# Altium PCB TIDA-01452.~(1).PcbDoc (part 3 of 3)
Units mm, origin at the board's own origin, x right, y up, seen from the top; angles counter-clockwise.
Board outline 60 x 40 mm, 6 copper layers (Top Layer, IN1-GND, IN2, IN3-POWER, IN4-GND, Bottom Layer), stack 1.532 mm thick; 268 components, 172 nets, 850 pads, 525 vias.

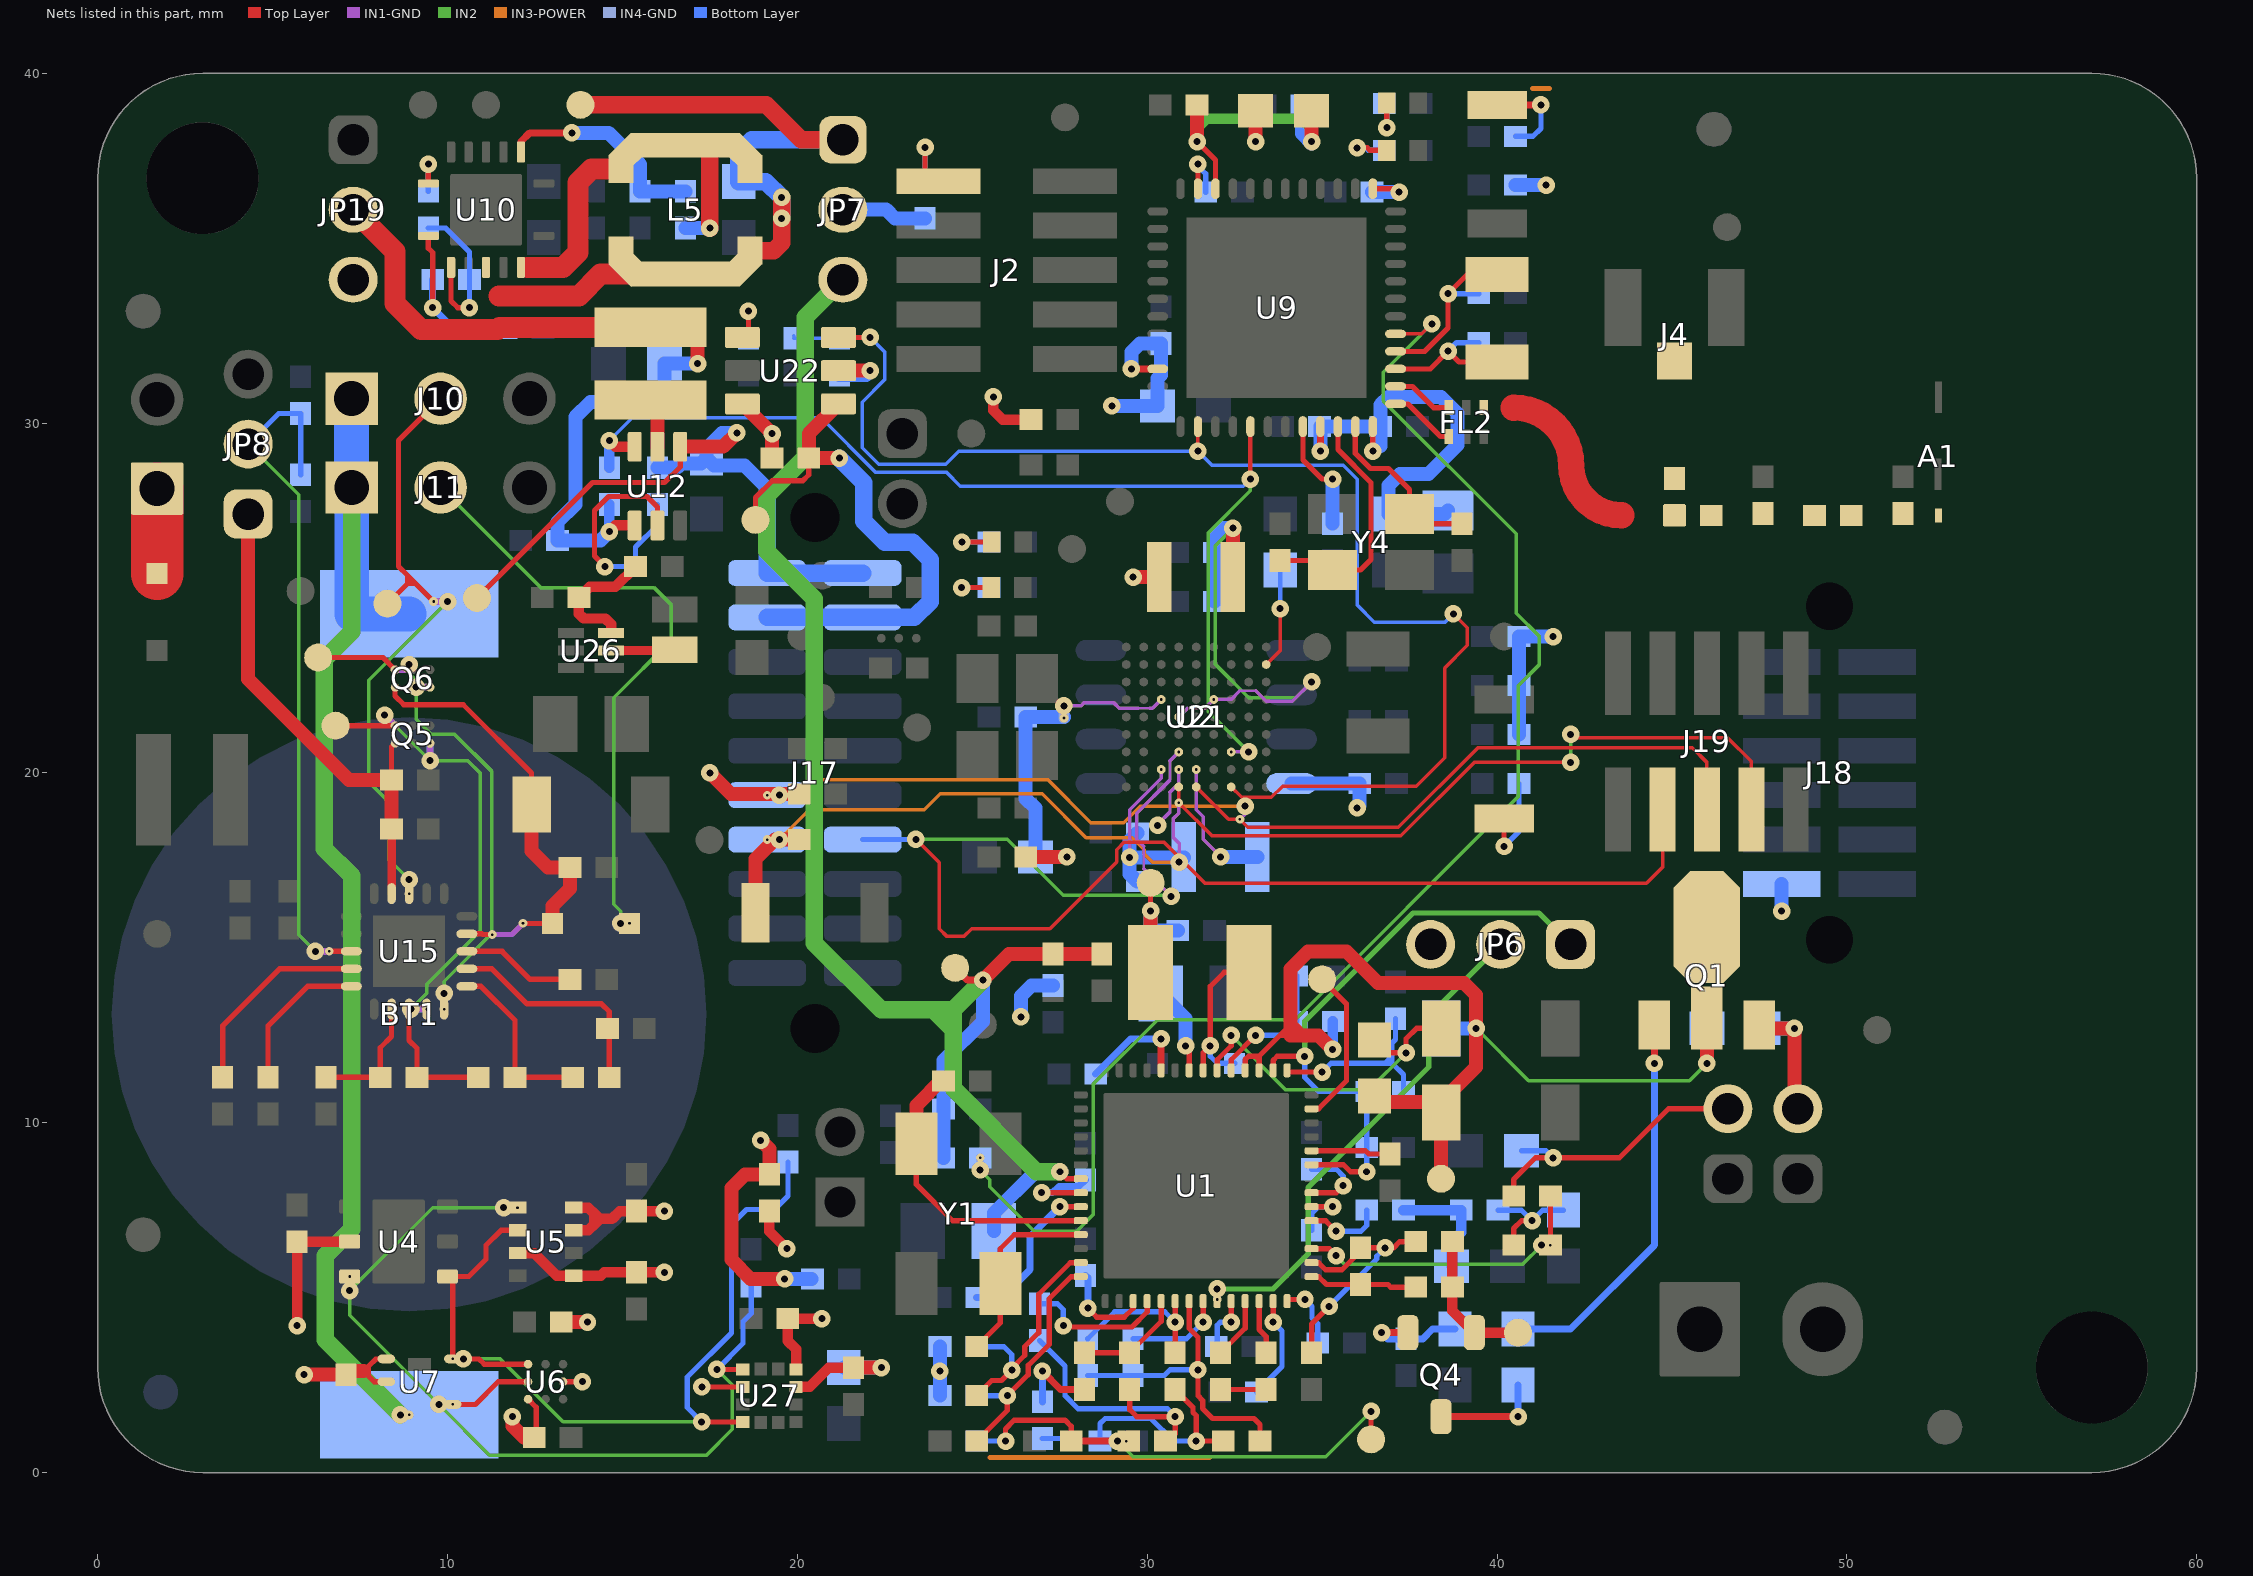
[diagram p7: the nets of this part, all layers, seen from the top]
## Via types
v1: diameter 0.4/0.5/0.5/0.5/0.5/0.4 (per signal layer), hole 0.2, Top Layer to Bottom Layer, 266 vias
v2: diameter 0.25/0.25 (per signal layer), hole 0.075, Top Layer to IN1-GND, tented top, 102 vias
v3: diameter 0.5/0.5/0.5/0.5 (per signal layer), hole 0.2, IN1-GND to IN4-GND, 75 vias
v4: diameter 0.25/0.25 (per signal layer), hole 0.075, IN4-GND to Bottom Layer, tented bottom, 55 vias
v5: diameter 0.5, hole 0.2, Top Layer to Bottom Layer, 21 vias
v6: diameter 0.25/0.2 (per signal layer), hole 0.075, Top Layer to IN1-GND, tented top, 5 vias
v7: diameter 0.3, hole 0.075, IN4-GND to Bottom Layer, 1 vias

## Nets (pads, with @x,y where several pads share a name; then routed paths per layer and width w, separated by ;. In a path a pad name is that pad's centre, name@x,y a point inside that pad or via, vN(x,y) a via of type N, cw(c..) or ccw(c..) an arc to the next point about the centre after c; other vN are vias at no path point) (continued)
MSP432_SSM_SPI_CS: J17.14 J19.3 U2.D3 | length 41.8
  Top Layer w0.1: v1(23.39,18.1) 24.05,17.44 24.05,15.55 24.275,15.325 24.755,15.325 24.98,15.55 27.22,15.55 29.125,17.455 29.125,17.805 29.345,18.025 30.475,18.025 31.65,16.85 44.271,16.85 44.73,17.309 J19.3@44.73,18.95
  IN1-GND w0.082: 29.9,17.257 29.9,17.9 ; 30.65,19.8 30.65,20.35
  IN1-GND w0.1: 29.9,17.257 v3(30.687,16.47) ; 29.9,17.9 29.7,18.1 29.7,18.85 30.65,19.8 ; 30.65,20.35 v2(30.9,20.6)
  IN2 w0.1: v1(23.39,18.1) 26,18.1 27.6,16.5 30.657,16.5 v3(30.687,16.47)
  Bottom Layer w0.15: J17.14@21.865,18.095 v1@23.39,18.095
MSP432_SSM_SPI_MISO: J17.11 J19.5 U2.E1 | length 32.5
  Top Layer w0.1: U2.E1@31.4,19.6 32.325,18.675 v2(32.65,18.675) 32.875,18.45 37.18,18.45 39.455,20.725 45.575,20.725 46,20.3 J19.5@46,18.95
  IN1-GND w0.1: v2(32.65,18.675) 32.8,18.825 v3(32.8,19.05)
  IN3-POWER w0.1: v3(19.485,19.365) 19.865,19.365 20.3,19.8 27.166,19.8 28.386,18.58 29.33,18.58 29.8,19.05 v3(32.8,19.05)
  IN4-GND w0.2: v4(19.135,19.365) v3(19.485,19.365)
MSP432_SSM_SPI_MOSI: J17.13 J19.7 U2.D1 | length 35.6
  Top Layer w0.1: U2.D1@30.9,19.6 v2(30.9,19.15) 31.85,18.2 37.249,18.2 39.349,20.3 v1(42.1,20.3) ; v1(42.1,21.1) 42.2,21 46.6,21 47.27,20.33 J19.7@47.27,18.95
  IN1-GND w0.1: v2(30.9,19.15) 30.9,18.85 30.75,18.7 30.75,18.15 30.909,17.991 v3(30.909,17.45)
  IN2 w0.1: v1(42.1,20.3) v1(42.1,21.1)
  IN3-POWER w0.1: v3(19.485,18.095) 20.34,18.95 23.63,18.95 24.08,19.4 27,19.4 28.25,18.15 29.566,18.15 29.916,17.799 29.916,17.684 30.151,17.45 v3(30.909,17.45)
  IN4-GND w0.2: v4(19.135,18.095) v3(19.485,18.095)
MSP432_VSW_2: L3.1 U2.E2 | length 3.8
  IN1-GND w0.1: v2(31.4,20.1) 31.4,18.95 31.6,18.75 31.6,18.1 v1(32.1,17.6)
  Bottom Layer w0.4: v1(32.1,17.6) L3.1@33.15,17.6
NEN_BQ_7: R67.1 U15.5 | length 4.3
  Top Layer w0.15: R67.1@4.87,11.3 4.87,12.77 6,13.9 U15.5@7.25,13.9
NetA1_1: A1.1 C67.1 R43.2
NetBT1_2: BT1.2 BT1.3 J10.1 J11.1 | length 36.4
  IN2 w0.5: J11.1@7.261,28.16 7.261,24.036 6.48,23.255 6.48,17.84 7.261,17.059 7.261,6.961 6.5,6.2 6.5,3.8 v3(8.65,1.65)
  IN4-GND w0.125: v3(8.65,1.65) v4(8.9,1.65)
  Bottom Layer w1: J10.1@7.26,30.7 7.26,28.161 J11.1@7.261,28.16 7.261,24.55 BT1.2@8.9,24.55
NetC1_1: C1.1 U1.6 | length 1.8
  Top Layer w0.15: U1.6@34.7,7.6 v1(35.3,7.6)
  Bottom Layer w0.15: C1.1@34.7,6.925 34.7,7.4 34.9,7.6 v1(35.3,7.6)
NetC2_1: C2.1 U1.7 | length 2.2
  Top Layer w0.15: U1.7@34.7,8 35.4,8 v1(35.6,8.2)
  Bottom Layer w0.15: C2.1@34.7,8.675 35.405,8.675 35.6,8.48 v1(35.6,8.2)
NetC3_1: C3.1 JP6.1 R27.1 U1.9 U1.16 | length 18
  Top Layer w0.15: U1.16@33.6,11.5 33.6,11.782 33.718,11.9 v1(34.5,11.9) ; U1.9@34.7,8.8 35.61,8.8 35.81,8.6 v1(36.275,8.6)
  IN2 w0.15: v1(34.5,11.9) 34.5,12.9 37.599,15.999 41.201,15.999 JP6.1@42.1,15.1
  Bottom Layer w0.15: v1(34.5,11.9) 34.5,11.3 34.9,10.9 R27.1@36.275,10.9 C3.1@36.275,9.3 v1(36.275,8.6)
NetC4_1: C4.1 U1.10 | length 2.3
  Top Layer w0.15: U1.10@34.7,9.2 36.24,9.2 36.335,9.105 C4.1@36.94,9.105
NetC5_1: C5.1 U1.24 | length 3.2
  Top Layer w0.2: U1.24@30.4,11.5 v1(30.4,12.4)
  Bottom Layer w0.2: C5.1@28.525,11.4 29.525,12.4 v1(30.4,12.4)
NetC6_1: C6.1 U1.37 | length 4.6
  Top Layer w0.15: v1@27.55,7.6 U1.37@28.1,7.6
  Bottom Layer w0.2: C6.1@25.125,5 25.85,5 26.65,5.8 26.65,6.75 v1(27.5,7.6)
NetC8_1: C8.1 U1.55 | length 3
  Top Layer w0.15: v1(33.6,4.3) U1.55@33.6,4.9
  Bottom Layer w0.15: C8.1@33.125,2.31 33.85,3.035 33.85,4.05 v1(33.6,4.3)
NetC9_1: C9.1 U1.56 | length 1.9
  Top Layer w0.15: U1.56@34,4.9 34.05,4.95 v1(34.51,4.95)
  Bottom Layer w0.15: v1(34.51,4.95) 34.71,4.75 34.71,4.42 34.875,4.255 C9.1@34.875,3.7
NetC10_2: C10.2 U1.39 Y1.1 | length 5.5
  Top Layer w0.15: C10.2@25.125,3.6 25.8,4.275 Y1.1@25.8,5.4 25.8,6.4 26.2,6.8 U1.39@28.1,6.8
NetC11_1: C11.1 C12.1 Q1.2 Q1.4 R1.1 R5.1 R8.1 TP4.1 U1.17 U1.18 | length 31.7
  Top Layer w0.15: U1.18@32.8,11.5 32.8,11.807 32.893,11.9 33.107,11.9 ; U1.17@33.2,11.5 33.2,11.807 ; 34.1,12.5 33.8,12.5 ; 34.1,12.8 33.8,12.5 ; 33.107,11.9 33.2,11.807 ; 33.107,11.9 33.2,11.9 ; 33.2,11.807 33.2,11.9 ; 33.2,11.9 33.8,12.5
  Top Layer w0.4: v1(35.3,12.1) 34.9,12.5 34.4,12.5 ; R8.1@36.5,10.76 36.66,10.6 C12.1@38.4,10.6 ; TP4.1@38.4,8.4 C12.1@38.4,10.3 C12.1@38.4,10.6 ; v1(46,11.7) Q1.2@46,13 ; 34.1,12.8 34.1,12.5 34.4,12.5 ; 34.1,12.8 34.1,14.4 34.6,14.9 35.7,14.9 36.6,14 39.05,14 39.4,13.65 v1(39.4,12.7) 39.4,11.6 C12.1@38.4,10.6 ; 34.1,12.8 34.4,12.5
  IN2 w0.1: v1(39.4,12.7) 40.9,11.2 45.5,11.2 v1(46,11.7)
  Bottom Layer w0.3: v1(35.3,12.1) R5.1@35.3,12.9
  Bottom Layer w0.4: C11.1@38.4,12.7 v1(39.4,12.7) ; v1(46,11.7) R1.1@46,12.7
NetC13_1: C13.1 R8.2 U1.20 | length 9.8
  Top Layer w0.15: U1.20@32,11.5 32,11.8 32.4,12.2 v1(32.4,12.5) ; R8.2@36.5,12.36 36.86,12 v1(37.4,12) 37.4,12.4 37.7,12.7 C13.1@38.4,12.7
  IN2 w0.1: v1(32.4,12.5) 33.95,10.95 36.35,10.95 v1(37.4,12)
NetC14_2: C14.2 U1.38 Y1.3 | length 8.4
  Top Layer w0.15: Y1.3@23.4,9.4 23.4,8.234 24.434,7.2 U1.38@28.1,7.2
  Top Layer w0.4: Y1.3@23.4,9.4 23.4,10.5 C14.2@24.137,11.238
NetC16_1: C16.1 R10.2 U1.1 | length 3.1
  Top Layer w0.15: U1.1@34.7,5.6 34.9,5.6 35.125,5.375 C16.1@36.1,5.375 36.885,5.375 36.96,5.3 R10.2@37.675,5.3
NetC16_2: C16.2 C17.1 R11.2 U1.2 | length 7.3
  Top Layer w0.15: R11.2@34.7,3.425 34.7,4.25 v1(35.2,4.75) ; U1.2@34.7,6 34.9,6 35.1,5.8 35.566,5.8 36.1,6.334 C16.2@36.1,6.425 v1(36.8,6.425) 37.035,6.425 37.21,6.6 C17.1@37.675,6.6
  Bottom Layer w0.15: v1(35.2,4.75) 36.56,6.11 36.56,6.185 v1(36.8,6.425)
NetC17_2: C17.2 Q4.1 R10.1 TP5.1 | length 4.1
  Top Layer w0.3: C17.2@38.725,6.6 R10.1@38.725,5.3 38.725,4.625 Q4.1@39.35,4 TP5.1@40.6,4
NetC18_1: C18.1 C36.1 L2.2 U2.D5 U2.F6 | length 15.8
  Top Layer w0.4: L2.2@32.45,25.6 v1(32.45,27)
  IN1-GND w0.082: 31.15,21.85 31.65,21.85 ; 32.65,22.35 33.1,22.35
  IN1-GND w0.1: v2(30.9,21.6) 31.15,21.85 ; 31.65,21.85 v2(31.9,22.1) 32.4,22.1 32.65,22.35 ; 33.1,22.35 33.4,22.05 34.15,22.05 v3(34.7,22.6)
  IN2 w0.1: v1(32.45,27) 31.95,26.5 31.95,23.1 32.9,22.15 34.25,22.15 v3(34.7,22.6)
  Bottom Layer w0.4: C36.1@31.925,24.9 C18.1@31.925,26.3 31.925,26.785 32.14,27 v1(32.45,27)
NetC19_1: C19.1 Q4.2 R12.1 | length 3
  Top Layer w0.2: v1(36.7,4) Q4.2@37.45,4
  Bottom Layer w0.2: v1(36.7,4) 36.875,3.825 C19.1@37.4,3.825 37.885,3.825 38.16,4.1 R12.1@38.8,4.1
NetC20_1: C20.1 R14.2 R15.1 | length 3.2
  Top Layer w0.15: R14.2@40.475,6.5 40.475,6.975 40.7,7.2 v1(41,7.2)
  Bottom Layer w0.15: R15.1@40.025,7.5 40.7,7.5 v1(41,7.2) 41.3,7.5 C20.1@41.9,7.5
NetC21_1: C21.1 R15.2 R16.1 | length 3.4
  Bottom Layer w0.3: R16.1@37.325,7.5 R15.2@38.975,7.5 38.975,6.865 38.7,6.59 C21.1@38.7,5.9
NetC22_1: C22.1 U1.53 | length 1.8
  Top Layer w0.15: C22.1@32.1,3.425 32.8,4.125 U1.53@32.8,4.9
NetC22_2: C22.2 R18.1 | length 1.3
  Top Layer w0.15: C22.2@32.1,2.375 R18.1@33.4,2.375
NetC23_1: C23.1 U1.46 | length 4.1
  Top Layer w0.15: v1(27.6,4.2) 27.635,4.165 29.565,4.165 30,4.6 U1.46@30,4.9
  Bottom Layer w0.15: C23.1@26.92,4.825 27.435,4.825 27.6,4.66 v1(27.6,4.2)
NetC23_2: C23.2 C24.1 R20.1 | length 8.1
  Top Layer w0.15: R20.1@29.5,2.375 29.5,1.8 29.7,1.6 v1(30.8,1.6) 30.8,1.1 C24.1@30.562,0.863
  Bottom Layer w0.15: C23.2@26.92,3.775 27.65,3.045 27.65,2.2 28.025,1.825 30.575,1.825 v1(30.8,1.6)
NetC24_2: C24.2 C26.1 R19.2 TP8.1 | length 14.3
  Top Layer w0.15: v1(25.95,0.9) 25.95,1.25 26.2,1.5 27.65,1.5 27.825,1.325 C26.1@27.825,0.9 ; TP8.1@36.4,0.95 v1(36.4,1.75)
  Top Layer w0.2: C26.1@27.825,0.9 v2(29.4,0.9)
  IN1-GND w0.2: v3(29.15,0.9) v2(29.4,0.9)
  IN2 w0.1: v3(29.15,0.9) 29.6,0.45 35.1,0.45 v1(36.4,1.75)
  Bottom Layer w0.15: R19.2@25.125,0.9 v1(25.95,0.9)
NetC27_1: C27.1 R20.2 U1.47 | length 3.1
  Top Layer w0.15: C27.1@28.2,3.425 R20.2@29.5,3.425 30.4,4.325 U1.47@30.4,4.9
NetC27_2: C27.2 R21.2 | length 2.3
  Top Layer w0.2: v1(27,2.9) 27.525,2.375 C27.2@28.2,2.375
  Bottom Layer w0.2: R21.2@27,2.025 v1(27,2.9)
NetC28_1: C28.1 R22.2 U1.48 | length 4.4
  Top Layer w0.15: R22.2@30.8,3.425 v1(30.8,4.3) U1.48@30.8,4.9
  Bottom Layer w0.15: C28.1@28.3,3.825 29.075,4.6 30.5,4.6 v1(30.8,4.3)
NetC28_2: C28.2 C32.1 R23.2 U1.49 | length 8.8
  Top Layer w0.15: U1.49@31.2,4.9 31.2,4.12 31.45,3.87 v1(31.45,2.94) 31.45,2.199 31.585,2.064 31.585,1.832 31.867,1.55 33.05,1.55 33.225,1.375 R23.2@33.225,0.9
  Bottom Layer w0.15: C28.2@28.3,2.775 C32.1@29.6,2.775 30.485,2.775 30.65,2.94 v1(31.45,2.94)
NetC31_1: C31.1 R21.1 R22.1 R23.1 | length 7.8
  Top Layer w0.15: R22.1@30.8,2.375 31.31,1.865 31.31,1.718 31.4,1.628 v1(31.4,0.9) R23.1@32.175,0.9
  Bottom Layer w0.15: R21.1@27,0.975 27.785,0.975 27.86,0.9 C31.1@28.65,0.9 28.65,1.4 28.8,1.55 30.1,1.55 30.75,0.9 v1(31.4,0.9)
NetC32_2: C32.2 U1.50 | length 2.8
  Top Layer w0.15: v1(31.6,4.3) U1.50@31.6,4.9
  Bottom Layer w0.15: C32.2@29.6,3.825 31.125,3.825 v1(31.6,4.3)
NetC34_1: C34.1 U1.52 | length 1.6
  Top Layer w0.15: v1(32.4,4.3) U1.52@32.4,4.9
  Bottom Layer w0.15: C34.1@32,3.61 32,4.21 32.09,4.3 v1(32.4,4.3)
NetC40_1: C40.1 C41.1 L3.2 U2.C2 | length 6
  IN1-GND w0.1: v1(29.5,17.59) 29.5,18.95 30.4,19.85 v2(30.4,20.1)
  Bottom Layer w0.4: C41.1@29.725,16.89 29.5,17.115 v1(29.5,17.59) ; C40.1@29.725,18.29 29.5,18.065 v1(29.5,17.59) ; L3.2@31.05,17.59 v1(29.5,17.59)
NetC63_1: C63.1 U9.47 Y4.1 | length 5.1
  Top Layer w0.15: U9.47@35.95,29.9 35.95,29.134 36.384,28.7 36.9,28.7 37.5,28.1 Y4.1@37.5,27.4 37.775,27.125 C63.1@39,27.125
NetC64_1: C64.1 U9.46 Y4.3 | length 7
  Top Layer w0.15: C64.1@33.8,26.075 Y4.3@35.025,26.075 ; Y4.3@35.025,26 Y4.3@35.3,25.725 ; Y4.3@35.3,25.8 36.1,25.8 36.4,26.1 36.4,28.295 35.45,29.245 U9.46@35.45,29.9
NetC65_1: C65.1 U9.4 Y5.2 | length 5.3
  Top Layer w0.15: U9.4@37.1,32.05 37.93,32.05 38.6,32.72 v1(38.6,33.7) 39.15,34.25 Y5.2@40,34.25
  Bottom Layer w0.15: v1(38.6,33.7) C65.1@39.475,33.7
NetC66_1: C66.1 U9.3 Y5.1 | length 4.2
  Top Layer w0.15: U9.3@37.1,31.55 38.09,31.55 v1(38.6,32.06) 38.91,31.75 Y5.1@40,31.75
  Bottom Layer w0.15: v1(38.6,32.06) 38.84,32.3 C66.1@39.475,32.3
NetC69_1: C69.1 U9.23 | length 1.5
  Top Layer w0.15: U9.23@31.45,36.7 v1(31.45,37.4)
  Bottom Layer w0.15: v1@31.45,37.35 31.675,37.125 C69.1@31.675,36.6
NetC72_1: C72.1 JP7.1 L5.2 TP18.1 U10.11 | length 21.8
  Top Layer w0.5: TP18.1@13.8,39.1 19.11,39.1 20.11,38.1 JP7.1@21.3,38.1 ; L5.2@18.642,34.932 19.322,34.932 19.55,35.16 v1(19.55,35.85) v1(19.55,36.45)
  Top Layer w0.6: 11.465,33.64 13.76,33.64 14.379,34.259 L5.2@16.8,34.259
  Bottom Layer w0.5: v1(19.55,35.85) v1(19.55,36.45) 19.1,36.9 C72.1@18.325,36.9 18.325,37.725 18.7,38.1 JP7.1@21.3,38.1
NetC76_1: C76.1 C101.2 JP19.2 L6.1 R55.2 U12.1 | length 24.7
  Top Layer w0.3: v1(14.625,26.9) 14.8,27.075 U12.1@15.35,27.075
  Top Layer w0.4: L6.1@16,32.74 17.15,32.74 v1(17.15,31.7)
  Top Layer w0.6: JP19.2@7.3,36.1 8.5,34.9 8.5,33.416 9.241,32.675 11.425,32.675 11.49,32.74 L6.1@15.8,32.74 L6.1@16,32.74
  Bottom Layer w0.3: v1(14.625,26.9) R55.2@14.625,27.675
  Bottom Layer w0.4: v1(14.625,26.9) 14.375,26.65 C101.2@13.145,26.65 13.145,27.175 13.65,27.68 13.65,30.18 14.08,30.61 15.91,30.61 16.2,30.9 C76.1@16.2,31.7 v1(17.15,31.7)
NetC84_1: C84.1 R140.1 U26.3 | length 3.7
  Top Layer w0.3: U26.3@14.675,24.03 14.675,24.245 14.505,24.415 13.89,24.415 13.755,24.55 C84.1@13.755,25.01 14.065,25.32 14.795,25.32 R140.1@15.375,25.9
NetC110_1: C110.1 R42.2 R43.1
NetCR1_1: CR1.1 R32.2 | length 1.6
  Top Layer w0.15: v1(24.695,25.3) CR1.1@25.545,25.3
  Bottom Layer w0.15: v1(24.695,25.3) R32.2@25.475,25.3
NetCR2_1: CR2.1 R33.2 | length 1.6
  Top Layer w0.15: v1(24.7,26.6) CR2.1@25.55,26.6
  Bottom Layer w0.15: v1(24.7,26.6) R33.2@25.475,26.6
NetCR3_1: CR3.1 R37.2 | length 1.4
  Top Layer w0.15: v1(36.85,38.445) CR3.1@36.85,39.15
  Bottom Layer w0.15: R37.2@36.775,39.14 36.85,39.065 v1(36.85,38.445)
NetCR4_1: CR4.1 R38.2 | length 1.7
  Top Layer w0.15: v1(36,37.87) 36.29,37.87 36.36,37.8 CR4.1@36.85,37.8
  Bottom Layer w0.15: v1(36,37.87) 36.25,37.87 36.32,37.8 R38.2@36.775,37.8
NetD2_2: D2.2 J9.1 | length 2.4
  Top Layer w1.5: D2.2@1.7,25.7 J9.1@1.7,28.13
NetD3_1: D3.1 L1.1 U1.21 | length 4.8
  Top Layer w0.15: U1.21@31.6,11.5 31.6,12 v1(31.8,12.2) 31.8,13.9 32.2,14.3 L1.1@32.905,14.3
  Bottom Layer w0.15: v1(31.8,12.2) 31.8,11.9 32,11.7 D3.1@32.5,11.7
NetD4_2: D4.2 J11.2 | length 18.1
  IN1-GND w0.2: v3(14.95,15.7) v2(15.2,15.7)
  IN2 w0.1: J11.2@9.801,28.16 12.661,25.3 15.9,25.3 16.4,24.8 16.4,23.8 14.75,22.15 14.75,16.248 14.95,16.048 v3(14.95,15.7)
NetFL2_1: FL2.1 R41.1 R42.1 | length 4.8
  Top Layer w0.75: 40.477,30.443 cw(c40.477,28.802) 42.118,28.802 ccw(c43.555,28.802) 43.555,27.365
NetFL2_3: FL2.3 U9.2 | length 1.8
  Top Layer w0.15: U9.2@37.1,31.05 37.58,31.05 38.187,30.443 FL2.3@38.62,30.443
NetFL2_4: FL2.4 U9.1 | length 1.9
  Top Layer w0.15: U9.1@37.1,30.55 37.45,30.55 38.382,29.618 FL2.4@38.62,29.618
NetJ2_1: J2.1 R31.2 | length 2.3
  Top Layer w0.15: v1@23.65,37.89 v1(23.65,37.88) 23.65,37.01 23.745,36.915 J2.1@24.03,36.915
  Bottom Layer w0.15: R31.2@23.65,36.905 v1(23.65,37.88)
NetJ4_1: J4.1 R41.2 | length 0
NetJP6_2: JP6.2 U1.51 | length 14.4
  IN1-GND w0.2: v2(32,4.95) v3(32,5.25)
  IN2 w0.15: v3(32,5.25) 33.6,5.25 34.6,6.25 34.6,8.15 38.05,11.6 38.05,13.05 JP6.2@40.1,15.1
NetJP8_2: JP8.2 R49.2 R59.1 U15.3 | length 19.9
  Top Layer w0.15: v2(6.62,14.9) U15.3@7.25,14.9
  IN1-GND w0.2: v3(6.22,14.9) v2(6.62,14.9)
  IN2 w0.1: JP8.2@4.3,29.4 5.75,27.95 5.75,15.37 v3(6.22,14.9)
  Bottom Layer w0.15: JP8.2@4.3,29.4 5.175,30.275 R59.1@5.8,30.275 R49.2@5.8,28.525
NetJP24_2: JP24.2 Q1.3 R1.2 | length 4.3
  Top Layer w0.4: Q1.3@47.5,12.8 47.6,12.7 v1(48.5,12.7) 48.5,10.5 JP24.2@48.6,10.4
  Bottom Layer w0.4: R1.2@47.6,12.7 v1(48.5,12.7)
NetJP25_2: JP25.2 R13.1 R17.2 | length 8.4
  Top Layer w0.15: R13.1@40.475,7.9 40.475,8.375 41.1,9 v1(41.6,9) 43.5,9 44.9,10.4 JP25.2@46.6,10.4
  Bottom Layer w0.15: R17.2@40.7,9.2 41.4,9.2 v1(41.6,9)
NetL5_1: L5.1 R46.1 U10.13 | length 9
  Top Layer w0.2: U10.13@12.1,34.45 12.29,34.45
  Top Layer w0.5: L5.1@16.8,37.942 17.49,37.942 v1@17.49,35.575
  Top Layer w0.6: 12.29,34.45 13.3,34.45 13.73,34.88 13.73,36.88 14.118,37.268 L5.1@14.959,37.268
  Bottom Layer w0.4: R46.1@16.8,35.575 v1(17.5,35.575)
NetL6_2: L6.2 U12.5 | length 1.3
  Top Layer w0.4: U12.5@16,29.325 L6.2@16,30.66
NetL8_2: L8.2 U26.2 | length 1.8
  Top Layer w0.25: U26.2@14.675,23.5 16.475,23.5 L8.2@16.5,23.525
NetQ1_1: Q1.1 R9.2 | length 11.2
  Top Layer w0.2: v1(44.5,11.7) Q1.1@44.5,12.8
  Bottom Layer w0.2: R9.2@40.6,4.1 42.1,4.1 44.5,6.5 v1(44.5,11.7)
NetQ4_3: Q4.3 R9.1 | length 3.1
  Top Layer w0.2: Q4.3@38.4,1.6 v1(40.6,1.6)
  Bottom Layer w0.2: v1(40.6,1.6) R9.1@40.6,2.5
NetR5_2: R5.2 R7.1 U1.19 | length 3.9
  Top Layer w0.15: U1.19@32.4,11.5 32.4,11.8 v1(33.1,12.5)
  Bottom Layer w0.15: v1(33.1,12.5) 33.875,12.5 R5.2@34.275,12.9 R7.1@34.275,14.2
NetR13_2: R13.2 R14.1 U1.3 | length 8.6
  Top Layer w0.15: U1.3@34.7,6.4 35.2,6.4 v1(35.4,6.2) ; v2(41.525,6.5) R13.2@41.525,7.9
  IN1-GND w0.2: v3(41.275,6.5) v2(41.525,6.5)
  IN2 w0.1: v1(35.4,6.2) 35.65,5.95 40.725,5.95 v3(41.275,6.5)
NetR16_2: R16.2 U1.5 | length 2.2
  Top Layer w0.15: U1.5@34.7,7.2 35.1,7.2 v1(35.4,6.9)
  Bottom Layer w0.15: v1(35.4,6.9) 36.11,6.9 36.275,7.065 R16.2@36.275,7.5
NetR18_2: R18.2 U1.54 | length 1.6
  Top Layer w0.15: U1.54@33.2,4.9 33.2,4.09 33.4,3.89 R18.2@33.4,3.425
NetR25_2: R25.2 U2.J8 | length 2.9
  Top Layer w0.1: U2.J8@33.4,23.1 33.8,23.5 v1(33.8,24.7)
  Bottom Layer w0.125: v1(33.8,24.7) R25.2@33.8,25.8
NetR26_1: R26.1 R27.2 U1.15 | length 5.7
  Top Layer w0.15: U1.15@34,11.5 34.05,11.45 v1(35,11.45)
  Bottom Layer w0.15: v1(35,11.45) 35.25,11.7 36.789,11.7 ; R26.1@37.1,12.975 37.1,12.38 37,12.28 37,11.911 ; R27.2@37.325,10.9 37.325,11.375 37,11.7 ; 36.789,11.7 37,11.911 ; 36.789,11.7 37,11.7 ; 37,11.7 37,11.911
NetR30_2: R30.2 SW1.2 | length 3
  Top Layer w0.4: SW1.2@18.8,16 18.8,17.54 19.36,18.1 R30.2@20.05,18.1
NetR34_1: R34.1 SW2.2 | length 2.8
  Top Layer w0.15: v1(40.2,17.9) SW2.2@40.2,18.7
  Bottom Layer w0.15: v1(40.2,17.9) 40.625,18.325 R34.1@40.625,19.7
NetR39_1: R39.1 SW3.2 | length 2.8
  Top Layer w0.2: SW3.2@40,39.1 v1(41.255,39.1)
  Bottom Layer w0.15: R39.1@40.525,38.2 41.03,38.2 41.255,38.425 v1(41.255,39.1)
NetR45_2: R45.2 R46.2 U10.2 | length 6.3
  Top Layer w0.2: U10.2@12.1,37.75 12.1,38.05 12.35,38.3 v1(13.55,38.3)
  Bottom Layer w0.4: v1(13.55,38.3) 14.6,38.3 15.5,37.4 R45.2@15.5,36.625 R46.2@16.8,36.625
NetR54_1: R54.1 R56.1 U12.2 | length 7.2
  Top Layer w0.15: v1(14.5,25.9) 14.2,26.2 14.2,27.5 14.6,27.9 15.7,27.9 16,27.6 U12.2@16,27.075
  Bottom Layer w0.15: v1(14.5,25.9) R56.1@15.375,25.9 15.375,26.455 16,27.08 R54.1@16,27.675
NetR60_2: R60.2 U15.13 | length 3.3
  Top Layer w0.15: U15.13@10.55,14.9 11.56,14.9 12.36,14.1 R60.2@13.5,14.1
NetR80_1: R80.1 U9.5 | length 41.2
  Top Layer w0.1: U9.5@37.1,32.55 37.85,32.55 v1(38.14,32.84)
  IN2 w0.1: v3(25.225,8.65) 25.5,8.375 25.5,8.167 26.767,6.9 27.983,6.9 28.45,7.367 28.45,11.1 30.3,12.95 34.228,12.95 40.604,19.326 40.604,22.49 41.2,23.086 41.2,23.914 40.55,24.564 40.55,26.833 36.75,30.633 36.75,31.45 v1(38.14,32.84)
  IN4-GND w0.2: v3(25.225,8.65) v4(25.225,9)
NetR88_1: R88.1 R89.2 U10.9 | length 4.6
  Top Layer w0.15: U10.9@10.1,34.45 10.1,33.49 10.29,33.3 v1(10.625,33.3)
  Bottom Layer w0.15: R88.1@9.45,35.575 9.945,35.575 10.625,34.895 R89.2@10.625,34.1 v1(10.625,33.3)
NetR88_2: R88.2 U10.7 | length 1.3
  Top Layer w0.15: U10.7@9.45,36.85 v1(9.45,37.4)
  Bottom Layer w0.15: R88.2@9.45,36.625 v1(9.45,37.4)
NetR89_1: R89.1 R90.2 U10.8 | length 5.3
  Top Layer w0.15: U10.8@9.45,35.35 9.45,35 9.575,34.875 v1(9.575,33.3)
  Bottom Layer w0.2: R89.1@9.575,34.1 v1(9.575,33.3) 10.175,32.7 R90.2@11.675,32.7
NetR122_1: R122.1 U22.1 | length 1.6
  Top Layer w0.15: U22.1@18.425,32.45 18.6,32.625 v1(18.6,33.2)
  Bottom Layer w0.15: R122.1@18.6,32.425 v1(18.6,33.2)
NetTP32_1: TP32.1 U1.13 | length 4.5
  Top Layer w0.15: U1.13@34.7,10.4 34.9,10.4 35.7,11.2 35.7,13.4 TP32.1@35,14.1
OK_HYST_7: R62.1 R64.2 U15.11 | length 5.1
  Top Layer w0.15: U15.11@10.55,13.9 10.957,13.9 11.925,12.932 R62.1@11.925,11.3 R64.2@13.575,11.3
OK_PROG_7: R64.1 R65.2 U15.12 | length 6.5
  Top Layer w0.15: U15.12@10.55,14.4 11.27,14.4 12.27,13.4 14.4,13.4 14.625,13.175 R64.1@14.625,11.3
PWR_MGMT.SSM_5V_EN_1: R55.1 U2.G3 U9.41 U12.6 | length 31.8
  Top Layer w0.125: v1(32.95,28.4) U9.41@32.95,29.9
  Top Layer w0.3: v1(14.625,29.5) 14.8,29.325 U12.6@15.35,29.325
  IN1-GND w0.1: v2(32.4,20.6) v3(32.9,20.6)
  IN2 w0.1: v3(32.9,20.6) 31.75,21.75 31.75,26.866 32.95,28.066 v1(32.95,28.4)
  Bottom Layer w0.1: v1(14.625,29.5) 15.275,30.15 20.682,30.15 22.23,28.601 24.25,28.601 24.651,28.2 32.75,28.2 v1(32.95,28.4)
  Bottom Layer w0.3: R55.1@14.625,28.725 v1(14.625,29.5)
PWR_MGMT.SSM_PWR_NEN_1: R91.1 R93.2 U2.G1 U9.38 U22.6 | length 40.1
  Top Layer w0.1: v1(31.45,29.2) U9.38@31.45,29.9 ; U2.G1@32.4,19.6 32.7,19.3 33.55,19.3 33.875,19.625 37.693,19.625 38.5,20.432 38.5,23 39.15,23.65 39.15,24.15 v1(38.75,24.55)
  Top Layer w0.15: U22.6@21.175,32.45 v1(22.08,32.45)
  Bottom Layer w0.1: R93.2@19.9,32.425 R91.1@21.2,32.425 21.225,32.45 v1(22.08,32.45) 22.49,32.04 22.49,31.24 21.85,30.6 21.85,29.3 22.324,28.827 24.243,28.827 24.617,29.2 v1(31.45,29.2) 31.85,28.8 35.6,28.8 36,28.4 36,24.8 36.488,24.312 38.512,24.312 v1(38.75,24.55)
SCL_GPS_3: R119.2 U4.6 U5.4 U6.B3 U7.4 U27.1 | length 28
  Top Layer w0.15: v2(10.15,1.95) 10.8,1.95 11.45,2.6 U6.B3@12.3,2.6 ; v1(17.7,2.95) U27.1@18.437,2.95
  IN1-GND w0.2: v3(7.2,5.204) v2(7.2,5.604) ; v3(9.75,1.95) v2(10.15,1.95) ; v3(11.6,7.575) v2(12,7.575)
  IN2 w0.1: v3(11.6,7.575) 9.571,7.575 v3(7.2,5.204) 7.2,4.5 v3(9.75,1.95) 11.2,0.5 17.402,0.5 18.138,1.236 18.138,2.512 v1(17.7,2.95)
  Bottom Layer w0.15: v1(17.7,2.95) 18.447,3.697 18.447,4.312 18.68,4.545 R119.2@18.68,5.332
SDA_GPS_3: R118.2 U4.1 U5.3 U6.C3 U7.6 U27.4 | length 25.6
  Top Layer w0.15: U4.1@10,5.604 U4.1@10.15,5.604 ; U5.3@12,6.925 11.525,6.925 11.1,6.5 11.1,6.1 10.604,5.604 U4.1@10.15,5.604 ; U6.C3@12.3,3.1 11.05,3.1 10.9,3.25 v2(10.15,3.25) U4.1@10.15,5.604 ; v1(17.26,1.45) U27.4@18.437,1.45
  IN1-GND w0.2: v2(10.15,3.25) v3(10.45,3.25)
  IN2 w0.1: v3(10.45,3.25) 11.5,3.25 13.3,1.45 v1(17.26,1.45)
  Bottom Layer w0.15: v1(17.26,1.45) 16.85,1.86 16.85,2.73 18.113,3.993 18.113,7.087 18.544,7.518 19.342,7.518 19.73,7.905 R118.2@19.73,8.875
VB_PRI_ON_7: Q6.A2 Q6.C1 TP28.1 U15.10 | length 15
  Top Layer w0.15: TP28.1@6.3,23.3 8.15,23.3 v2(8.5,22.95)
  IN1-GND w0.2: v2(8.5,22.95) 8.75,22.95 v3(8.9,23.1) ; v3(9.1,22.45) v2(9.5,22.45) ; v2(9.9,13.25) v3(9.9,13.7)
  IN2 w0.1: v3(8.9,23.1) 8.9,22.85 9.1,22.65 v3(9.1,22.45) 9.1,21.534 9.534,21.1 10.21,21.1 11.27,20.04 11.27,15.42 9.9,14.05 v3(9.9,13.7)
VB_SEC_ON_7: Q5.A2 Q5.C1 TP24.1 U15.9 | length 14.1
  Top Layer w0.15: TP24.1@6.8,21.35 v2(8.5,21.35)
  IN1-GND w0.2: v3(8.2,21.65) v2(8.5,21.35) ; v3(8.95,13.25) v2(9.4,13.25) ; v3(9.5,20.35) v2(9.5,20.85)
  IN2 w0.1: v3(8.2,21.65) v3(9.5,20.35) 10.58,20.35 10.94,19.99 10.94,15.494 9.4,13.954 9.4,13.7 v3(8.95,13.25)
VBAT_OV_7: R61.1 R63.2 U15.7 | length 3.6
  Top Layer w0.15: R63.2@6.52,11.3 R61.1@8.075,11.3 8.075,12.143 8.4,12.468 U15.7@8.4,13.25
VBAT_PRI_7: C82.1 C83.1 D4.1 Q6.C2 U15.14 | length 13
  Top Layer w0.15: Q6.C2@8.5,22.45 8.5,22.2 8.75,21.95 10.45,21.95 12.4,20 C83.1@12.4,19.1 ; U15.14@10.55,15.4 10.98,15.4 11,15.38 v2(11.28,15.38) ; v2(12.157,15.7) D4.1@13,15.7
  Top Layer w0.4: C83.1@12.4,19.1 12.4,17.775 12.875,17.3 C82.1@13.5,17.3 13.5,16.7 13,16.2 D4.1@13,15.7
  IN1-GND w0.15: v2(11.28,15.38) 11.837,15.38 v2(12.157,15.7)
VBAT_SEC_7: J10.2 TP27.1 U15.18 | length 18.1
  Top Layer w0.15: TP27.1@8.28,24.84 8.86,25.42 ; v2(9.6,24.9) 9.08,25.42 ; J10.2@9.8,30.7 8.6,29.5 8.6,25.9 8.86,25.64 ; 8.86,25.42 8.86,25.64 ; 8.86,25.42 9.08,25.42 ; 8.86,25.64 9.08,25.42
  IN1-GND w0.2: v2(8.9,16.55) v3(8.9,16.95) ; v2(9.6,24.9) v3(10,24.9)
  IN2 w0.1: v3(8.9,16.95) 8.32,17.53 8.32,19.17 7.75,19.74 7.75,22.65 v3(10,24.9)
VCC_5V: C75.1 J17.1 J17.2 R54.2 TP22.1 U12.4 | length 19.7
  Top Layer w0.15: TP22.1@10.84,25 14.14,28.3 16.2,28.3 16.65,28.75 U12.4@16.65,29.325
  Top Layer w0.4: U12.4@16.65,29.325 17.875,29.325 v1(18.27,29.72)
  Bottom Layer w0.4: R54.2@16,28.725 16.565,28.725 16.68,28.84 17.24,28.84 C75.1@17.4,29 ; v1(18.27,29.72) 17.85,29.72 17.4,29.27 C75.1@17.4,29 ; 19.13,28.15 18.49,28.79 17.61,28.79 C75.1@17.4,29
  Bottom Layer w0.5: 19.135,28.065 J17.1@19.135,25.715 J17.2@21.865,25.715
VCC_GPS: C47.1 C48.1 C49.1 C50.1 C51.1 C111.1 C112.1 C113.1 R36.1 R96.1 U4.5 U5.2 U5.5 U5.6 U5.8 U6.A3 U6.B1 U7.1 U7.2 U27.2 U27.9 U27.10 | length 28.3
  Top Layer w0.15: U7.2@8.25,2.6 7.9,2.6 7.739,2.76 ; U7.1@8.25,3.25 7.95,3.25 7.739,3.039 ; U6.A3@12.3,2.1 12.535,1.865 12.535,1.06 C50.1@12.475,1 ; U6.B1@13.3,2.6 v1(13.85,2.6) ; v1(17.27,2.45) U27.2@18.437,2.45 ; 7.739,2.76 7.739,3.039 ; 7.739,2.76 7.6,2.9 7.739,3.039
  Top Layer w0.3: v1(5.7,4.2) C47.1@5.7,6.6 5.704,6.604 U4.5@7.2,6.604 ; U5.2@12,6.275 12.475,6.275 13.125,5.625 U5.8@13.6,5.625 14.383,5.625 14.483,5.725 C48.1@15.4,5.725 v1(16.2,5.725) ; U5.6@13.6,6.925 14.025,6.925 14.2,7.1 ; U5.5@13.6,7.575 14.025,7.575 14.2,7.4 ; v1(16.2,7.475) C49.1@15.4,7.475 14.925,7.475 14.7,7.25 14.35,7.25 ; R96.1@19.2,7.475 19.2,6.9 v1(19.7,6.4) ; U27.9@19.963,2.45 20.35,2.45 20.9,3 C112.1@21.6,3 ; U27.10@19.963,2.95 19.963,3.525 19.725,3.763 C111.1@19.725,4.4 v1(20.7,4.4) ; 14.2,7.1 14.2,7.4 ; 14.2,7.1 14.35,7.25 ; 14.2,7.4 14.35,7.25
  Top Layer w0.4: v1(5.9,2.8) C51.1@7.1,2.8 7.2,2.9 7.6,2.9 ; v1(11.85,1.6) 11.85,1.33 12.18,1 C50.1@12.475,1 ; R36.1@13.25,4.3 v1(14,4.3) ; C112.1@21.6,3 v1(22.4,3)
  Bottom Layer w0.4: C113.1@21.325,3.005 21.33,3 v1(22.4,3)
VCC_MAIN: C37.1 C38.1 C39.1 C98.1 FL1.1 J18.11 JP7.2 JP19.3 L2.1 R24.1 R29.1 R31.1 R35.1 R40.1 R91.2 R95.2 R96.2 R109.1 R110.1 U2.C6 U2.D2 U21.8 U22.3 U22.5 | length 38.6
  Top Layer w0.4: v1(17.5,20) 18.1,19.4 R24.1@20.05,19.4 ; U22.3@18.425,30.55 v1(19.275,29.7) R95.2@19.275,29 ; v1(18.95,9.5) 19.2,9.25 R96.2@19.2,8.525 18.499,8.525 18.11,8.136 18.11,6.089 18.66,5.539 v1(19.634,5.539) ; U22.5@21.175,31.5 v1(22.08,31.5) ; C39.1@26.525,17.6 v1(27.7,17.6) ; v1(29.6,25.6) L2.1@30.35,25.6 ; v1(33.1,38.05) FL1.1@33.1,38.93
  IN1-GND w0.082: 29.74,21.85 30.07,21.85 ; 30.65,18.883 30.65,19.45
  IN1-GND w0.1: v3(27.62,21.92) 28.11,21.92 28.19,22 29.05,22 29.2,21.85 29.74,21.85 ; 30.07,21.85 30.15,21.85 v2(30.4,22.1) ; v3(30.3,18.5) 30.3,18.533 30.65,18.883 ; 30.65,19.45 30.9,19.7 v2(30.9,20.1)
  IN3-POWER w0.15: 41.02,39.568 41.49,39.568
  IN4-GND w0.3: v4(27.62,21.57) v3(27.62,21.92)
  Bottom Layer w0.4: v1(19.634,5.539) R29.1@20.409,5.539 ; R91.2@21.2,31.375 21.955,31.375 v1(22.08,31.5) ; JP7.2@21.3,36.1 22.54,36.1 22.785,35.855 R31.1@23.65,35.855 ; v4@27.62,21.6 C37.1@26.525,21.6 26.525,19.275 26.8,19 C38.1@26.8,17.6 v1(27.7,17.6) ; U21.8@34.125,19.695 36.075,19.695 36.075,19.075 v1(36,19) ; R40.1@40.525,36.8 v1(41.4,36.8) ; R35.1@40.625,21.1 R109.1@40.625,22.5 R110.1@40.625,23.9 v1(41.6,23.9) ; v1(48.135,16.05) J18.11@48.135,16.825
VCC_SSM: J17.3 J17.4 R95.1 TP1.1 U22.4 | length 16.2
  Top Layer w0.15: TP1.1@18.8,27.235 18.8,27.87 19.28,28.35 20.15,28.35 20.325,28.525 R95.1@20.325,29
  Top Layer w0.4: U22.4@21.175,30.55 20.325,29.7 R95.1@20.325,29 v1(21.2,29)
  Bottom Layer w0.5: J17.3@19.135,24.445 J17.4@21.865,24.445 23.345,24.445 23.8,24.9 23.8,26.1 23.3,26.6 22.5,26.6 21.9,27.2 21.9,28.3 v1(21.2,29)
VCCIO_CFG1_5: R84.1 R85.1 U1.41 | length 6.9
  Top Layer w0.15: R85.1@25.125,2.2 25.555,2.63 25.83,2.63 v1(26.13,2.93) 26.13,2.985 26.5,3.355 26.5,3.6 26.9,4 26.9,5.1 27.8,6 U1.41@28.1,6
  Bottom Layer w0.15: R84.1@25.125,3.6 25.9,3.6 26.13,3.37 v1(26.13,2.93)
VCCIO_CFG2_5: R86.1 R87.2 U1.42 | length 7
  Top Layer w0.15: R87.2@25.125,0.9 26,1.775 v1(26,2.2) 26.6,2.8 26.6,3.066 27.2,3.666 27.2,4.977 27.823,5.6 U1.42@28.1,5.6
  Bottom Layer w0.15: R86.1@25.125,2.2 v1(26,2.2)
VCCIO_DAC: C15.2 JP7.3 R28.1 R80.2 R131.1 R132.1 TP11.1 U1.35 | length 47.2
  Top Layer w0.15: v1(27.5,8.6) 27.7,8.4 U1.35@28.1,8.4
  Top Layer w0.2: TP11.1@24.51,14.43 24.865,14.075 v1(25.3,14.075)
  Top Layer w0.4: v1(25.3,14.075) 26.05,14.825 R132.1@27.3,14.825 R131.1@28.7,14.825
  IN2 w0.5: JP7.3@21.3,34.1 20.22,33.02 20.22,29.026 19.124,27.93 19.124,26.338 20.489,24.974 20.489,15.136 22.4,13.225 23.89,13.225 ; v1(25.3,14.075) 24.45,13.225 ; v1(27.5,8.6) 26.834,8.6 24.45,10.984 24.45,12.665 ; 23.89,13.225 24.45,13.225 ; 23.89,13.225 24.45,12.665 ; 24.45,12.665 24.45,13.225
  Bottom Layer w0.4: R80.2@24.175,9 R28.1@24.175,10.4 24.175,11.775 25.3,12.9 v1(25.3,14.075) ; C15.2@25.616,6.9 25.616,7.416 26.8,8.6 v1(27.5,8.6)
VDDR: C60.1 C61.1 C62.2 L4.2 U9.45 U9.48 | length 13.5
  Top Layer w0.15: v1(36.45,29.2) U9.48@36.45,29.9
  Top Layer w0.2: v1(34.95,29.2) U9.45@34.95,29.9
  Bottom Layer w0.4: v1(34.95,29.2) 34.95,29.9 C62.2@36.6,29.9 ; v1(36.45,29.2) v1@36.6,29.35 ; 36.675,29.35 C62.2@36.675,29.9 36.675,30.525 36.9,30.75 38.4,30.75 38.87,30.28 38.87,29.38 38.04,28.55 37.229,28.55 36.9,28.221 C60.1@36.9,27.4 38.5,27.4 L4.2@38.6,27.5
VDDS: C55.1 C56.1 C57.1 C58.1 C59.1 C100.1 FL1.2 R44.1 U9.13 U9.22 U9.34 U9.44 | length 20.8
  Top Layer w0.15: v1(31.425,38.05) 31.95,37.525 U9.22@31.95,36.7 ; U9.44@34.45,29.9 34.45,28.95 35,28.4 v1(35.3,28.4) ; U9.13@36.45,36.7 37.1,36.7 v1(37.2,36.6)
  Top Layer w0.2: v1(29.55,31.55) U9.34@30.3,31.55
  Top Layer w0.3: v1(25.6,30.75) 25.6,30.37 25.87,30.1 R44.1@26.675,30.1
  Top Layer w0.4: v1(31.425,38.05) C56.1@31.425,39.1 ; v1(34.7,38.05) FL1.2@34.7,38.93
  IN2 w0.3: v1(31.425,38.05) 31.425,38.425 31.7,38.7 34.4,38.7 34.7,38.4 v1(34.7,38.05) v1@34.7,38
  Bottom Layer w0.4: v1(28.99,30.49) C58.1@30.29,30.49 30.29,31.27 30.4,31.38 C100.1@30.4,32.275 29.79,32.275 29.55,32.035 v1(29.55,31.55) ; C55.1@34.425,39.1 34.425,38.275 v1@34.7,38 ; C59.1@35.3,27.125 v1(35.3,28.4) ; C57.1@36.425,36.6 v1(37.2,36.6)
VINL_5: C25.1 C29.1 C30.1 C33.1 C35.1 JP6.3 L1.2 R84.2 R86.2 TP6.1 U1.22 U1.36 U1.45 | length 22.9
  Top Layer w0.15: v1(26.98,8) U1.36@28.1,8 ; v1(28.3,4.7) 28.56,4.44 29.34,4.44 29.6,4.7 U1.45@29.6,4.9 ; v1(30.095,16.06) TP6.1@30.095,16.86 ; v1(31.1,12.2) 31.2,12.1 U1.22@31.2,11.5
  Top Layer w0.4: L1.2@30.095,14.3 v1(30.095,16.06)
  IN3-POWER w0.15: 25.509,0.432 31.783,0.432
  Bottom Layer w0.2: v1(26.98,8) 27.299,8 27.474,8.175 28.04,8.175 C35.1@28.23,8.365 ; C33.1@28.24,5.635 28.3,5.575 v1(28.3,4.7)
  Bottom Layer w0.4: R86.2@24.075,2.2 v1(24.075,2.9) R84.2@24.075,3.6 ; v1(26.39,13.03) 26.39,13.62 26.695,13.925 C25.1@27.3,13.925 ; C29.1@30.084,14 C29.1@30.095,13.989 ; v1(30.095,16.06) 30.095,15.5 ; C30.1@30.875,15.5 30.095,15.5 ; v1(31.1,12.2) 31.1,12.984 C29.1@30.384,13.7 C29.1@30.095,13.989 ; C29.1@30.095,13.989 30.095,15.5
VRDIV_7: R61.2 R62.2 U15.8 | length 3.7
  Top Layer w0.15: U15.8@8.9,13.25 8.9,12.354 9.125,12.129 R61.2@9.125,11.3 ; R61.2@9.2,11.3 R62.2@10.875,11.3
VREF_SAMP_7: C81.1 U15.4 | length 5.8
  Top Layer w0.15: C81.1@3.57,11.3 3.57,12.77 5.2,14.4 U15.4@7.25,14.4
VSTOR_7: C77.1 C78.1 JP8.1 Q5.C2 U15.19 | length 14.4
  Top Layer w0.15: C77.1@8.4,19.8 8.4,20.75 Q5.C2@8.5,20.85
  Top Layer w0.24: U15.19@8.4,16.55 C78.1@8.4,18.4
  Top Layer w0.4: JP8.1@4.3,27.4 4.3,22.68 7.18,19.8 C77.1@8.4,19.8 C78.1@8.4,18.4
pads on no net: 1.0 2.0 3.0 4.0 5.0 6.0 7.0 8.0 J2.7 J17.18 J17.MH J18.0 Q5.B1 Q5.B2 Q6.B1 Q6.B2 Q7.B1 Q7.B2 U1.14 U1.33 U1.34 U1.43 U1.44 U2.A4 U2.A7 U2.A8 U2.B1 U2.B4 U2.C5 U2.C9 U2.D7 U2.D9 U2.E7 U2.E8 U2.E9 U2.F3 U2.F9 U2.G4 U2.G5 U2.G6 U2.H1 U2.H2 U2.H3 U2.H4 U2.H5 U2.J1 U2.J2 U2.J3 U2.J4 U2.J9 U4.3 U4.4 U4.7 U7.5 U9.6 U9.12 U9.39 U10.10 U10.15@10.54,35.54 U10.15@10.54,36.66 U10.15@11.66,35.54 U10.15@11.66,36.66 U21.7 U26.5 U27.11

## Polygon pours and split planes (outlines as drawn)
NetC72_1 on Top Layer "Polysolid" (solid, remove dead copper, pour order 11): 22,37.4 14.6,37.4 14.6,38.9 15.05,39.35 21.65,39.35 21.8,39.2 22,39
GND on Top Layer "Polysolid" (solid, remove dead copper, pour order 12): 0,40 0,0 60,0 60,38.3 58.3,40
VCC_GPS on IN3-POWER "Polysolid" (solid, remove dead copper, pour order 15): 19.2,7.8 0,7.8 0,0 22.7,0 22.7,6.9 21.8,7.8 20.9,7.8
VINL_5 on IN3-POWER "Polysolid" (solid, remove dead copper, pour order 16): 23,0 23,14.85 23.45,15.3 24.85,16.7 34.25,16.7 43.172,16.7 43.65,16.222 43.65,0
VDDS on IN3-POWER "Polysolid" (solid, remove dead copper, pour order 14): 35.95,28 36.55,28 37.6,29.05 37.6,36.45 37.6,37.7 37.45,37.85 36.663,38.637 34.637,38.637 34.15,38.15 33.5,37.5 32.7,37.5 31.85,38.35 31.2,38.35 29.85,38.35 27.5,36 25.2,33.7 25.2,30.35 27.55,28
VCC_MAIN on IN3-POWER "Polysolid" (solid, remove dead copper, pour order 17): 0,8.1 21.95,8.1 23,7.05 23,0 60,0 60,40 0,40
GND on IN1-GND "Polysolid" (solid, remove dead copper, pour order 13): 0,40 0,0 60,0 60,38.3 58.3,40
GND on IN4-GND "Polysolid" (solid, remove dead copper, pour order 18): 0,40 0,0 60,0 60,38.3 58.3,40
GND on Bottom Layer "Polysolid" (solid, remove dead copper, pour order 20): 0,40 0,0 60,0 60,38.3 58.3,40
GND on IN2 "Polysolid" (solid, remove dead copper, pour order 19): 0,40 0,0 60,0 60,38.3 58.3,40

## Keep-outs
Keep-Out Layer:
  circle w0.5: c3,37 r1.6
  circle w0.5: c57,3 r1.6
  lines w0.5: 0,3 ccw(c3,3) 3,0 57,0 ccw(c57,3) 60,3 60,37 ccw(c57,37) 57,40 3,40 ccw(c3,37) 0,37 0,3.008

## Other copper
Top Layer:
  rectangle net GND: 50.56,28.47 52.505,31.67
  region net NetJ4_1: 45.45,28.09 45.45,30.933 45.575,31.25 45.575,31.775 44.575,31.775 44.575,31.25 44.7,30.933 44.7,28.09
  pour cut-out: 51.9,26.334 52.505,26.334 52.505,27.14 51.9,27.14
  pour cut-out: 45.4,26.334 45.8,26.334 45.8,26.99 45.4,26.99
  pour cut-out: 49.4,28.396 49.4,26.334 49.8,26.334 49.8,28.396
  pour cut-out: 17.79,2.29 18.06,2.02 18.06,1.89 17.79,1.62 17.79,1.57 18.12,1.57 18.65,1.04 18.79,1.04 18.89,1.14 19.02,1.14 19.12,1.04 19.79,1.04 19.9,1.15 20.04,1.15 20.15,1.04 20.25,1.04 20.35,1.14 20.35,2.053 20.548,2.252 18.218,2.252 18.18,2.29
  pour cut-out: 52.505,40 52.505,0 60,0 60,40
  region net NetC72_1: 10.98,33.69 11.33,33.34 11.63,33.34 11.63,33.79 11.22,34.2 11.22,34.63 10.98,34.63
  region net LBOOST_7: 7.8,16.4 7.11,17.09 7.808,17.788 8.02,17.576 8.02,16.4
  pour cut-out: 38.37,29.28 37.826,29.28 36.768,30.338 37.672,30.338 38.37,29.64
  region net NetFL2_1: 39.62,30.443 39.62,30.655 39.745,30.655 40.427,30.817 40.49,30.817 40.49,30.443
  region net NetFL2_1: 39.62,30.443 39.62,30.23 39.745,30.23 40.429,30.067 40.49,30.067 40.49,30.443
  region net NetFL2_1: 45.4,27.74 43.555,27.74 43.555,26.99 45.4,26.99
  region net NetC110_1: 45.8,26.99 49.4,26.99 49.4,27.74 45.8,27.74
  region net NetA1_1: 49.8,26.99 51.9,26.99 52.505,27.14 52.615,27.14 52.615,27.575 52.505,27.575 51.9,27.74 49.8,27.74
  pour cut-out: -0.07,16.32 1.23,16.32 2,15.55 7.25,15.55 7.25,14.48 7.9,13.83 8.4,13.83 8.4,13.4 9.9,13.4 10.55,14.05 10.55,15.62 10.73,15.8 11.472,15.8 12.297,16.625 16.195,16.625 17.1,15.72 17.1,10.59 16.2,9.69 15.14,9.69 14.31,8.86 -0.06,8.86
  pour cut-out: 0,37 ccw(c3,37) 3,34 ccw(c3,37) 6,37 ccw(c3,37) 3,40 ccw(c3,37)
  pour cut-out: 54,3 ccw(c57,3) 57,0 ccw(c57,3) 60,3 ccw(c57,3) 57,6 ccw(c57,3)
IN1-GND:
  pour cut-out: 39.12,29.322 39.603,28.839 40.193,28.839 40.58,28.452 40.58,27.48 42.172,25.889 52.505,25.889 52.505,40 41.915,40 41.915,35.351 41.68,35.116 41.681,32.228 41.175,31.722 41.175,31.231 40.994,31.05 39.382,31.05 39.12,30.788
  pour cut-out: 60,0 52.505,0 52.505,40 60,40
IN2:
  pour cut-out: 60,0 52.505,0 52.505,40 60,40
IN3-POWER:
  pour cut-out: 60,0 52.505,0 52.505,40 60,40
  pour cut-out: 29.02,31.55 ccw(c29.55,31.55) 29.55,31.02 ccw(c29.55,31.55) 30.08,31.55 ccw(c29.55,31.55) 29.55,32.08 ccw(c29.55,31.55)
IN4-GND:
  pour cut-out: 60,0 52.505,0 52.505,40 60,40
Bottom Layer:
  pour cut-out: 60,0 52.505,0 52.505,40 60,40
  pour cut-out: 0,37 ccw(c3,37) 3,34 ccw(c3,37) 6,37 ccw(c3,37) 3,40 ccw(c3,37)
  pour cut-out: 54,3 ccw(c57,3) 57,0 ccw(c57,3) 60,3 ccw(c57,3) 57,6 ccw(c57,3)

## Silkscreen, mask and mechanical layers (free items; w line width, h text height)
Top Overlay:
  circle w0.25: c7.6,4 r0.1
  circle w0.25: c10.6,5.6 r0.1
  circle w0.25: c6.35,15.9 r0.1
  circle w0.25: c13.5,36.85 r0.1
  circle w0.25: c17.65,32.45 r0.1
  circle w0.25: c17.15,2.95 r0.1
  circle w0.25: c13.8,2 r0.1
  circle w0.25: c11.05,5.15 r0.1
  circle w0.4: c24.12,38.53 r0.1
  circle w0.25: c37.79,30.38 r0.1
  circle w0.25: c35.7,4.2 r0.1
  circle w0.25: c43.45,17.2 r0.1
  lines w0.15: 17.585,30.015 17.845,30.015 ; 17.62,29.63 17.62,29.79 17.845,30.015 ; 17.845,29.755 17.845,30.015
  lines w0.2: 0.327,35.638 ccw(c3,37) 4.362,39.673 ; 55.638,0.327 cw(c57,3) 59.673,4.362
  text "DEBUG" at 16.544,10.723 h0.8
  text "Rev.B" at 59.2,7.8 h0.8 r90
Bottom Overlay:
  circle w0.25: c46.8,24.37 r0.1
  circle w0.25: c27.45,19.7 r0.1
  lines w0.2: 0.327,35.638 ccw(c3,37) 4.362,39.673 ; 17.67,19.35 17.67,13.31 18.825,13.31 ; 17.67,20.64 17.67,24.34 17.34,24.34 17.34,26.14 17.67,26.14 17.67,26.39 ; 22.175,13.31 23.33,13.31 23.33,13.83 ; 22.175,26.69 23.33,26.69 23.33,22.91 ; 23.33,14.73 23.33,15.57 ; 55.638,0.327 cw(c57,3) 59.673,4.362 ; 46.02,21.905 46.02,23.875 48.44,23.875 48.44,25.84 50.56,25.84 50.56,23.875 52.3,23.875 52.3,16.125 50.56,16.125 50.56,14.16 48.44,14.16 48.44,16.125 46.7,16.125 46.7,21.905 46.02,21.905
Board:
  lines w0.15: 0,3 ccw(c3,3) 3,0 57,0 ccw(c57,3) 60,3 60,37 ccw(c57,37) 57,40 3,40 ccw(c3,37) 0,37 0,3.008
  lines w0.2: 8.326,-16.255 ccw(c9.596,-16.255) 9.596,-17.525 52.58,-17.525 ccw(c52.58,-16.255) 53.85,-16.255 53.85,-8.445 ccw(c52.58,-8.445) 52.58,-7.175 9.596,-7.175 ccw(c9.596,-8.445) 8.326,-8.445 8.326,-16.255
Mechanical 4:
  lines w0.1: 18.337,12.066 22.591,12.066 22.591,27.941 18.337,27.941 18.337,12.066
